VERSION 5.7 ;
BUSBITCHARS "[]" ;
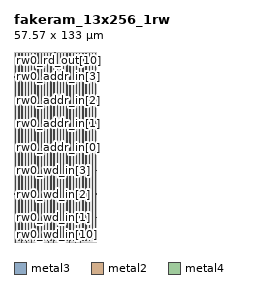
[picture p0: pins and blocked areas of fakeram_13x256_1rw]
MACRO fakeram_13x256_1rw
  FOREIGN fakeram_13x256_1rw 0 0 ;
  SYMMETRY X Y R90 ;
  SIZE 57.570 BY 133.000 ;
  CLASS BLOCK ;
  PIN rw0_wd_in[0]
    DIRECTION INPUT ;
    USE SIGNAL ;
    SHAPE ABUTMENT ;
    PORT
      LAYER metal3 ;
      RECT 0.000 0.805 0.210 0.875 ;
    END
  END rw0_wd_in[0]
  PIN rw0_wd_in[1]
    DIRECTION INPUT ;
    USE SIGNAL ;
    SHAPE ABUTMENT ;
    PORT
      LAYER metal3 ;
      RECT 0.000 17.185 0.210 17.255 ;
    END
  END rw0_wd_in[1]
  PIN rw0_wd_in[2]
    DIRECTION INPUT ;
    USE SIGNAL ;
    SHAPE ABUTMENT ;
    PORT
      LAYER metal3 ;
      RECT 0.000 33.565 0.210 33.635 ;
    END
  END rw0_wd_in[2]
  PIN rw0_wd_in[3]
    DIRECTION INPUT ;
    USE SIGNAL ;
    SHAPE ABUTMENT ;
    PORT
      LAYER metal3 ;
      RECT 0.000 49.945 0.210 50.015 ;
    END
  END rw0_wd_in[3]
  PIN rw0_wd_in[4]
    DIRECTION INPUT ;
    USE SIGNAL ;
    SHAPE ABUTMENT ;
    PORT
      LAYER metal3 ;
      RECT 57.360 0.805 57.570 0.875 ;
    END
  END rw0_wd_in[4]
  PIN rw0_wd_in[5]
    DIRECTION INPUT ;
    USE SIGNAL ;
    SHAPE ABUTMENT ;
    PORT
      LAYER metal3 ;
      RECT 57.360 17.185 57.570 17.255 ;
    END
  END rw0_wd_in[5]
  PIN rw0_wd_in[6]
    DIRECTION INPUT ;
    USE SIGNAL ;
    SHAPE ABUTMENT ;
    PORT
      LAYER metal3 ;
      RECT 57.360 33.565 57.570 33.635 ;
    END
  END rw0_wd_in[6]
  PIN rw0_wd_in[7]
    DIRECTION INPUT ;
    USE SIGNAL ;
    SHAPE ABUTMENT ;
    PORT
      LAYER metal2 ;
      RECT 1.105 0.000 1.175 0.210 ;
    END
  END rw0_wd_in[7]
  PIN rw0_wd_in[8]
    DIRECTION INPUT ;
    USE SIGNAL ;
    SHAPE ABUTMENT ;
    PORT
      LAYER metal2 ;
      RECT 4.905 0.000 4.975 0.210 ;
    END
  END rw0_wd_in[8]
  PIN rw0_wd_in[9]
    DIRECTION INPUT ;
    USE SIGNAL ;
    SHAPE ABUTMENT ;
    PORT
      LAYER metal2 ;
      RECT 8.705 0.000 8.775 0.210 ;
    END
  END rw0_wd_in[9]
  PIN rw0_wd_in[10]
    DIRECTION INPUT ;
    USE SIGNAL ;
    SHAPE ABUTMENT ;
    PORT
      LAYER metal2 ;
      RECT 12.505 0.000 12.575 0.210 ;
    END
  END rw0_wd_in[10]
  PIN rw0_wd_in[11]
    DIRECTION INPUT ;
    USE SIGNAL ;
    SHAPE ABUTMENT ;
    PORT
      LAYER metal2 ;
      RECT 16.305 0.000 16.375 0.210 ;
    END
  END rw0_wd_in[11]
  PIN rw0_wd_in[12]
    DIRECTION INPUT ;
    USE SIGNAL ;
    SHAPE ABUTMENT ;
    PORT
      LAYER metal2 ;
      RECT 20.105 0.000 20.175 0.210 ;
    END
  END rw0_wd_in[12]
  PIN rw0_rd_out[0]
    DIRECTION OUTPUT ;
    USE SIGNAL ;
    SHAPE ABUTMENT ;
    PORT
      LAYER metal2 ;
      RECT 23.905 0.000 23.975 0.210 ;
    END
  END rw0_rd_out[0]
  PIN rw0_rd_out[1]
    DIRECTION OUTPUT ;
    USE SIGNAL ;
    SHAPE ABUTMENT ;
    PORT
      LAYER metal2 ;
      RECT 27.705 0.000 27.775 0.210 ;
    END
  END rw0_rd_out[1]
  PIN rw0_rd_out[2]
    DIRECTION OUTPUT ;
    USE SIGNAL ;
    SHAPE ABUTMENT ;
    PORT
      LAYER metal2 ;
      RECT 31.505 0.000 31.575 0.210 ;
    END
  END rw0_rd_out[2]
  PIN rw0_rd_out[3]
    DIRECTION OUTPUT ;
    USE SIGNAL ;
    SHAPE ABUTMENT ;
    PORT
      LAYER metal2 ;
      RECT 35.305 0.000 35.375 0.210 ;
    END
  END rw0_rd_out[3]
  PIN rw0_rd_out[4]
    DIRECTION OUTPUT ;
    USE SIGNAL ;
    SHAPE ABUTMENT ;
    PORT
      LAYER metal2 ;
      RECT 39.105 0.000 39.175 0.210 ;
    END
  END rw0_rd_out[4]
  PIN rw0_rd_out[5]
    DIRECTION OUTPUT ;
    USE SIGNAL ;
    SHAPE ABUTMENT ;
    PORT
      LAYER metal2 ;
      RECT 42.905 0.000 42.975 0.210 ;
    END
  END rw0_rd_out[5]
  PIN rw0_rd_out[6]
    DIRECTION OUTPUT ;
    USE SIGNAL ;
    SHAPE ABUTMENT ;
    PORT
      LAYER metal2 ;
      RECT 46.705 0.000 46.775 0.210 ;
    END
  END rw0_rd_out[6]
  PIN rw0_rd_out[7]
    DIRECTION OUTPUT ;
    USE SIGNAL ;
    SHAPE ABUTMENT ;
    PORT
      LAYER metal2 ;
      RECT 1.105 132.790 1.175 133.000 ;
    END
  END rw0_rd_out[7]
  PIN rw0_rd_out[8]
    DIRECTION OUTPUT ;
    USE SIGNAL ;
    SHAPE ABUTMENT ;
    PORT
      LAYER metal2 ;
      RECT 6.615 132.790 6.685 133.000 ;
    END
  END rw0_rd_out[8]
  PIN rw0_rd_out[9]
    DIRECTION OUTPUT ;
    USE SIGNAL ;
    SHAPE ABUTMENT ;
    PORT
      LAYER metal2 ;
      RECT 12.125 132.790 12.195 133.000 ;
    END
  END rw0_rd_out[9]
  PIN rw0_rd_out[10]
    DIRECTION OUTPUT ;
    USE SIGNAL ;
    SHAPE ABUTMENT ;
    PORT
      LAYER metal2 ;
      RECT 17.635 132.790 17.705 133.000 ;
    END
  END rw0_rd_out[10]
  PIN rw0_rd_out[11]
    DIRECTION OUTPUT ;
    USE SIGNAL ;
    SHAPE ABUTMENT ;
    PORT
      LAYER metal2 ;
      RECT 23.145 132.790 23.215 133.000 ;
    END
  END rw0_rd_out[11]
  PIN rw0_rd_out[12]
    DIRECTION OUTPUT ;
    USE SIGNAL ;
    SHAPE ABUTMENT ;
    PORT
      LAYER metal2 ;
      RECT 28.655 132.790 28.725 133.000 ;
    END
  END rw0_rd_out[12]
  PIN rw0_addr_in[0]
    DIRECTION INPUT ;
    USE SIGNAL ;
    SHAPE ABUTMENT ;
    PORT
      LAYER metal3 ;
      RECT 0.000 66.325 0.210 66.395 ;
    END
  END rw0_addr_in[0]
  PIN rw0_addr_in[1]
    DIRECTION INPUT ;
    USE SIGNAL ;
    SHAPE ABUTMENT ;
    PORT
      LAYER metal3 ;
      RECT 0.000 82.705 0.210 82.775 ;
    END
  END rw0_addr_in[1]
  PIN rw0_addr_in[2]
    DIRECTION INPUT ;
    USE SIGNAL ;
    SHAPE ABUTMENT ;
    PORT
      LAYER metal3 ;
      RECT 0.000 99.085 0.210 99.155 ;
    END
  END rw0_addr_in[2]
  PIN rw0_addr_in[3]
    DIRECTION INPUT ;
    USE SIGNAL ;
    SHAPE ABUTMENT ;
    PORT
      LAYER metal3 ;
      RECT 0.000 115.465 0.210 115.535 ;
    END
  END rw0_addr_in[3]
  PIN rw0_addr_in[4]
    DIRECTION INPUT ;
    USE SIGNAL ;
    SHAPE ABUTMENT ;
    PORT
      LAYER metal3 ;
      RECT 57.360 49.945 57.570 50.015 ;
    END
  END rw0_addr_in[4]
  PIN rw0_addr_in[5]
    DIRECTION INPUT ;
    USE SIGNAL ;
    SHAPE ABUTMENT ;
    PORT
      LAYER metal3 ;
      RECT 57.360 66.325 57.570 66.395 ;
    END
  END rw0_addr_in[5]
  PIN rw0_addr_in[6]
    DIRECTION INPUT ;
    USE SIGNAL ;
    SHAPE ABUTMENT ;
    PORT
      LAYER metal3 ;
      RECT 57.360 82.705 57.570 82.775 ;
    END
  END rw0_addr_in[6]
  PIN rw0_addr_in[7]
    DIRECTION INPUT ;
    USE SIGNAL ;
    SHAPE ABUTMENT ;
    PORT
      LAYER metal3 ;
      RECT 57.360 99.085 57.570 99.155 ;
    END
  END rw0_addr_in[7]
  PIN rw0_we_in
    DIRECTION INPUT ;
    USE SIGNAL ;
    SHAPE ABUTMENT ;
    PORT
      LAYER metal2 ;
      RECT 34.165 132.790 34.235 133.000 ;
    END
  END rw0_we_in
  PIN rw0_ce_in
    DIRECTION INPUT ;
    USE SIGNAL ;
    SHAPE ABUTMENT ;
    PORT
      LAYER metal2 ;
      RECT 39.675 132.790 39.745 133.000 ;
    END
  END rw0_ce_in
  PIN rw0_clk
    DIRECTION INPUT ;
    USE SIGNAL ;
    SHAPE ABUTMENT ;
    PORT
      LAYER metal2 ;
      RECT 45.185 132.790 45.255 133.000 ;
    END
  END rw0_clk
  PIN VSS
    DIRECTION INOUT ;
    USE GROUND ;
    PORT
      LAYER metal4 ;
      RECT 1.000 0.840 1.280 132.160 ;
      RECT 3.240 0.840 3.520 132.160 ;
      RECT 5.480 0.840 5.760 132.160 ;
      RECT 7.720 0.840 8.000 132.160 ;
      RECT 9.960 0.840 10.240 132.160 ;
      RECT 12.200 0.840 12.480 132.160 ;
      RECT 14.440 0.840 14.720 132.160 ;
      RECT 16.680 0.840 16.960 132.160 ;
      RECT 18.920 0.840 19.200 132.160 ;
      RECT 21.160 0.840 21.440 132.160 ;
      RECT 23.400 0.840 23.680 132.160 ;
      RECT 25.640 0.840 25.920 132.160 ;
      RECT 27.880 0.840 28.160 132.160 ;
      RECT 30.120 0.840 30.400 132.160 ;
      RECT 32.360 0.840 32.640 132.160 ;
      RECT 34.600 0.840 34.880 132.160 ;
      RECT 36.840 0.840 37.120 132.160 ;
      RECT 39.080 0.840 39.360 132.160 ;
      RECT 41.320 0.840 41.600 132.160 ;
      RECT 43.560 0.840 43.840 132.160 ;
      RECT 45.800 0.840 46.080 132.160 ;
      RECT 48.040 0.840 48.320 132.160 ;
      RECT 50.280 0.840 50.560 132.160 ;
      RECT 52.520 0.840 52.800 132.160 ;
      RECT 54.760 0.840 55.040 132.160 ;
      RECT 57.000 0.840 57.280 132.160 ;
    END
  END VSS
  PIN VDD
    DIRECTION INOUT ;
    USE POWER ;
    PORT
      LAYER metal4 ;
      RECT 1.000 0.840 1.280 132.160 ;
      RECT 3.240 0.840 3.520 132.160 ;
      RECT 5.480 0.840 5.760 132.160 ;
      RECT 7.720 0.840 8.000 132.160 ;
      RECT 9.960 0.840 10.240 132.160 ;
      RECT 12.200 0.840 12.480 132.160 ;
      RECT 14.440 0.840 14.720 132.160 ;
      RECT 16.680 0.840 16.960 132.160 ;
      RECT 18.920 0.840 19.200 132.160 ;
      RECT 21.160 0.840 21.440 132.160 ;
      RECT 23.400 0.840 23.680 132.160 ;
      RECT 25.640 0.840 25.920 132.160 ;
      RECT 27.880 0.840 28.160 132.160 ;
      RECT 30.120 0.840 30.400 132.160 ;
      RECT 32.360 0.840 32.640 132.160 ;
      RECT 34.600 0.840 34.880 132.160 ;
      RECT 36.840 0.840 37.120 132.160 ;
      RECT 39.080 0.840 39.360 132.160 ;
      RECT 41.320 0.840 41.600 132.160 ;
      RECT 43.560 0.840 43.840 132.160 ;
      RECT 45.800 0.840 46.080 132.160 ;
      RECT 48.040 0.840 48.320 132.160 ;
      RECT 50.280 0.840 50.560 132.160 ;
      RECT 52.520 0.840 52.800 132.160 ;
      RECT 54.760 0.840 55.040 132.160 ;
      RECT 57.000 0.840 57.280 132.160 ;
    END
  END VDD
  OBS
    LAYER metal1 ;
    RECT 0 0 57.570 133.000 ;
    LAYER metal2 ;
    RECT 0 0 57.570 133.000 ;
    LAYER metal3 ;
    RECT 0 0 57.570 133.000 ;
    LAYER metal4 ;
    RECT 0 0 57.570 133.000 ;
    LAYER OVERLAP ;
    RECT 0 0 57.570 133.000 ;
  END
END fakeram_13x256_1rw

END LIBRARY
